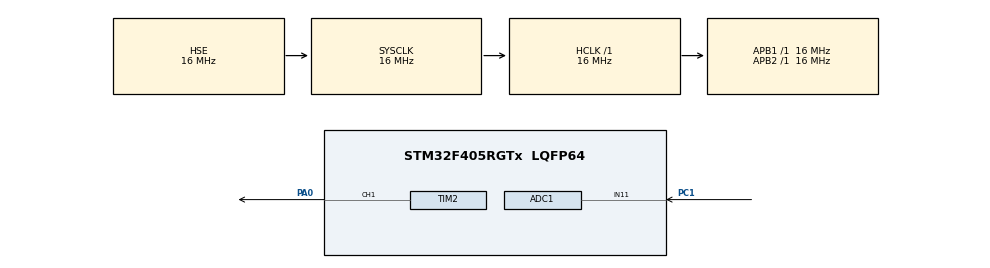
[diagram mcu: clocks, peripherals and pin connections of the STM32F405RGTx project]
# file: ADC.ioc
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ADC1.Channel-1\#ChannelRegularConversion=ADC_CHANNEL_11
ADC1.NbrOfConversionFlag=1
ADC1.Rank-1\#ChannelRegularConversion=1
ADC1.SamplingTime-1\#ChannelRegularConversion=ADC_SAMPLETIME_3CYCLES
ADC1.master=1
Mcu.Family=STM32F4
Mcu.Name=STM32F405RGTx
Mcu.Package=LQFP64
NVIC.ADC_IRQn=true\:0\:0\:false\:false\:true\:true\:true\:true
NVIC.PriorityGroup=NVIC_PRIORITYGROUP_4
NVIC.TIM2_IRQn=true\:0\:0\:false\:false\:true\:true\:true\:true
PA0-WKUP.Signal=S_TIM2_CH1_ETR
PA13.Mode=Serial_Wire
PA13.Signal=SYS_JTMS-SWDIO
PA14.Mode=Serial_Wire
PA14.Signal=SYS_JTCK-SWCLK
PC1.Signal=ADCx_IN11
PH0-OSC_IN.Mode=HSE-External-Oscillator
PH0-OSC_IN.Signal=RCC_OSC_IN
PH1-OSC_OUT.Mode=HSE-External-Oscillator
PH1-OSC_OUT.Signal=RCC_OSC_OUT
ProjectManager.HeapSize=0x200
ProjectManager.StackSize=0x400
ProjectManager.TargetToolchain=MDK-ARM V5.32
RCC.AHBFreq_Value=16000000
RCC.APB1Freq_Value=16000000
RCC.APB2Freq_Value=16000000
RCC.CortexFreq_Value=16000000
RCC.HSE_VALUE=16000000
RCC.HSI_VALUE=16000000
RCC.LSE_VALUE=32768
RCC.PLLSourceVirtual=RCC_PLLSOURCE_HSE
RCC.SYSCLKFreq_VALUE=16000000
RCC.SYSCLKSource=RCC_SYSCLKSOURCE_HSE
RCC.VCOOutputFreq_Value=192000000
SH.ADCx_IN11.0=ADC1_IN11,IN11
SH.S_TIM2_CH1_ETR.0=TIM2_CH1,PWM Generation1 CH1
TIM2.AutoReloadPreload=TIM_AUTORELOAD_PRELOAD_ENABLE
TIM2.Channel-PWM\ Generation1\ CH1=TIM_CHANNEL_1
TIM2.Period=65535
VP_TIM2_VS_ClockSourceINT.Mode=Internal
board=custom

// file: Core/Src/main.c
/* USER CODE BEGIN Header */
/**
  ******************************************************************************
  * @file           : main.c
  * @brief          : Main program body
  ******************************************************************************
  * @attention
  *
  * Copyright (c) 2023 STMicroelectronics.
  * All rights reserved.
  *
  * This software is licensed under terms that can be found in the LICENSE file
  * in the root directory of this software component.
  * If no LICENSE file comes with this software, it is provided AS-IS.
  *
  ******************************************************************************
  */
/* USER CODE END Header */
#include "main.h"

ADC_HandleTypeDef hadc1;

TIM_HandleTypeDef htim2;

void SystemClock_Config(void);
static void MX_GPIO_Init(void);
static void MX_ADC1_Init(void);
static void MX_TIM2_Init(void);

/* USER CODE BEGIN 0 */
 uint16_t ad_res = 0;
/* USER CODE END 0 */

int main(void)
{
  /* USER CODE BEGIN 1 */

    HAL_Init();
    SystemClock_Config();
    MX_GPIO_Init();
    MX_ADC1_Init();
    MX_TIM2_Init();
    HAL_TIM_PWM_Start(&htim2, TIM_CHANNEL_1);
  /* USER CODE END 1 */

  /* MCU Configuration--------------------------------------------------------*/

  /* Reset of all peripherals, Initializes the Flash interface and the Systick. */
  HAL_Init();

  /* Configure the system clock */
  SystemClock_Config();

  /* Initialize all configured peripherals */
  MX_GPIO_Init();
  MX_ADC1_Init();
  MX_TIM2_Init();

  /* Infinite loop */
  while (1)
  {
    HAL_ADC_Start(&hadc1);
		HAL_ADC_PollForConversion(&hadc1,1);
		ad_res = HAL_ADC_GetValue(&hadc1);
        TIM2->CCR1 = (ad_res<<4);
        HAL_Delay(1);

  }
}

void HAL_ADC_ConvCpltCallback(ADC_HandleTypeDef* hadc)
{
    ad_res = HAL_ADC_GetValue(&hadc1);
}
void SystemClock_Config(void)
{
  RCC_OscInitTypeDef RCC_OscInitStruct = {0};
  RCC_ClkInitTypeDef RCC_ClkInitStruct = {0};

  /** Configure the main internal regulator output voltage
  */
  __HAL_RCC_PWR_CLK_ENABLE();
  __HAL_PWR_VOLTAGESCALING_CONFIG(PWR_REGULATOR_VOLTAGE_SCALE1);

  /** Initializes the RCC Oscillators according to the specified parameters
  * in the RCC_OscInitTypeDef structure.
  */
  RCC_OscInitStruct.OscillatorType = RCC_OSCILLATORTYPE_HSE;
  RCC_OscInitStruct.HSEState = RCC_HSE_ON;
  RCC_OscInitStruct.PLL.PLLState = RCC_PLL_NONE;
  if (HAL_RCC_OscConfig(&RCC_OscInitStruct) != HAL_OK)
  {
    Error_Handler();
  }

  /** Initializes the CPU, AHB and APB buses clocks
  */
  RCC_ClkInitStruct.ClockType = RCC_CLOCKTYPE_HCLK|RCC_CLOCKTYPE_SYSCLK
                              |RCC_CLOCKTYPE_PCLK1|RCC_CLOCKTYPE_PCLK2;
  RCC_ClkInitStruct.SYSCLKSource = RCC_SYSCLKSOURCE_HSE;
  RCC_ClkInitStruct.AHBCLKDivider = RCC_SYSCLK_DIV1;
  RCC_ClkInitStruct.APB1CLKDivider = RCC_HCLK_DIV1;
  RCC_ClkInitStruct.APB2CLKDivider = RCC_HCLK_DIV1;

  if (HAL_RCC_ClockConfig(&RCC_ClkInitStruct, FLASH_LATENCY_0) != HAL_OK)
  {
    Error_Handler();
  }
}

static void MX_ADC1_Init(void)
{

  ADC_ChannelConfTypeDef sConfig = {0};

  /** Configure the global features of the ADC (Clock, Resolution, Data Alignment and number of conversion)
  */
  hadc1.Instance = ADC1;
  hadc1.Init.ClockPrescaler = ADC_CLOCK_SYNC_PCLK_DIV2;
  hadc1.Init.Resolution = ADC_RESOLUTION_12B;
  hadc1.Init.ScanConvMode = DISABLE;
  hadc1.Init.ContinuousConvMode = DISABLE;
  hadc1.Init.DiscontinuousConvMode = DISABLE;
  hadc1.Init.ExternalTrigConvEdge = ADC_EXTERNALTRIGCONVEDGE_NONE;
  hadc1.Init.ExternalTrigConv = ADC_SOFTWARE_START;
  hadc1.Init.DataAlign = ADC_DATAALIGN_RIGHT;
  hadc1.Init.NbrOfConversion = 1;
  hadc1.Init.DMAContinuousRequests = DISABLE;
  hadc1.Init.EOCSelection = ADC_EOC_SINGLE_CONV;
  if (HAL_ADC_Init(&hadc1) != HAL_OK)
  {
    Error_Handler();
  }

  /** Configure for the selected ADC regular channel its corresponding rank in the sequencer and its sample time.
  */
  sConfig.Channel = ADC_CHANNEL_11;
  sConfig.Rank = 1;
  sConfig.SamplingTime = ADC_SAMPLETIME_3CYCLES;
  if (HAL_ADC_ConfigChannel(&hadc1, &sConfig) != HAL_OK)
  {
    Error_Handler();
  }

}

static void MX_TIM2_Init(void)
{

  TIM_ClockConfigTypeDef sClockSourceConfig = {0};
  TIM_MasterConfigTypeDef sMasterConfig = {0};
  TIM_OC_InitTypeDef sConfigOC = {0};

  htim2.Instance = TIM2;
  htim2.Init.Prescaler = 0;
  htim2.Init.CounterMode = TIM_COUNTERMODE_UP;
  htim2.Init.Period = 65535;
  htim2.Init.ClockDivision = TIM_CLOCKDIVISION_DIV1;
  htim2.Init.AutoReloadPreload = TIM_AUTORELOAD_PRELOAD_ENABLE;
  if (HAL_TIM_Base_Init(&htim2) != HAL_OK)
  {
    Error_Handler();
  }
  sClockSourceConfig.ClockSource = TIM_CLOCKSOURCE_INTERNAL;
  if (HAL_TIM_ConfigClockSource(&htim2, &sClockSourceConfig) != HAL_OK)
  {
    Error_Handler();
  }
  if (HAL_TIM_PWM_Init(&htim2) != HAL_OK)
  {
    Error_Handler();
  }
  sMasterConfig.MasterOutputTrigger = TIM_TRGO_RESET;
  sMasterConfig.MasterSlaveMode = TIM_MASTERSLAVEMODE_DISABLE;
  if (HAL_TIMEx_MasterConfigSynchronization(&htim2, &sMasterConfig) != HAL_OK)
  {
    Error_Handler();
  }
  sConfigOC.OCMode = TIM_OCMODE_PWM1;
  sConfigOC.Pulse = 0;
  sConfigOC.OCPolarity = TIM_OCPOLARITY_HIGH;
  sConfigOC.OCFastMode = TIM_OCFAST_DISABLE;
  if (HAL_TIM_PWM_ConfigChannel(&htim2, &sConfigOC, TIM_CHANNEL_1) != HAL_OK)
  {
    Error_Handler();
  }
  HAL_TIM_MspPostInit(&htim2);

}

static void MX_GPIO_Init(void)
{
  GPIO_InitTypeDef GPIO_InitStruct = {0};

  /* GPIO Ports Clock Enable */
  __HAL_RCC_GPIOH_CLK_ENABLE();
  __HAL_RCC_GPIOC_CLK_ENABLE();
  __HAL_RCC_GPIOA_CLK_ENABLE();

  /*Configure GPIO pin Output Level */
  HAL_GPIO_WritePin(GPIOA, LED_2_Pin|LED_1_Pin, GPIO_PIN_RESET);

  /*Configure GPIO pin : SWITCH_3_Pin */
  GPIO_InitStruct.Pin = SWITCH_3_Pin;
  GPIO_InitStruct.Mode = GPIO_MODE_INPUT;
  GPIO_InitStruct.Pull = GPIO_NOPULL;
  HAL_GPIO_Init(SWITCH_3_GPIO_Port, &GPIO_InitStruct);

  /*Configure GPIO pins : SWITCH_2_Pin SWITCH_1_Pin */
  GPIO_InitStruct.Pin = SWITCH_2_Pin|SWITCH_1_Pin;
  GPIO_InitStruct.Mode = GPIO_MODE_INPUT;
  GPIO_InitStruct.Pull = GPIO_NOPULL;
  HAL_GPIO_Init(GPIOA, &GPIO_InitStruct);

  /*Configure GPIO pins : LED_2_Pin LED_1_Pin */
  GPIO_InitStruct.Pin = LED_2_Pin|LED_1_Pin;
  GPIO_InitStruct.Mode = GPIO_MODE_OUTPUT_PP;
  GPIO_InitStruct.Pull = GPIO_NOPULL;
  GPIO_InitStruct.Speed = GPIO_SPEED_FREQ_LOW;
  HAL_GPIO_Init(GPIOA, &GPIO_InitStruct);

}

void Error_Handler(void)
{
  __disable_irq();
  while (1)
  {
  }
}
